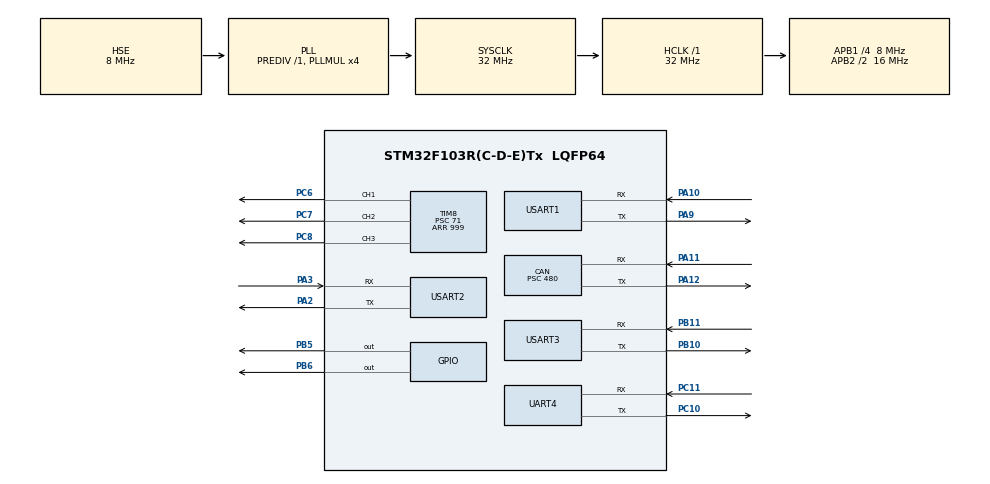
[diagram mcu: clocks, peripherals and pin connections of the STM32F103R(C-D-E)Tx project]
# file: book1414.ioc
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CAN.BS1=CAN_BS1_3TQ
CAN.BS2=CAN_BS2_2TQ
CAN.CalculateBaudRate=2777
CAN.CalculateTimeBit=360000
CAN.CalculateTimeQuantum=60000.0
CAN.Mode=CAN_MODE_LOOPBACK
CAN.Prescaler=480
Mcu.Family=STM32F1
Mcu.Name=STM32F103R(C-D-E)Tx
Mcu.Package=LQFP64
NVIC.PriorityGroup=NVIC_PRIORITYGROUP_4
NVIC.TIM3_IRQn=true\:0\:0\:false\:false\:true\:true\:true\:true
NVIC.TIM8_UP_IRQn=true\:2\:0\:true\:false\:true\:true\:true\:true
NVIC.UART4_IRQn=true\:0\:0\:false\:false\:true\:true\:true\:true
NVIC.USART3_IRQn=true\:0\:0\:false\:false\:true\:true\:true\:true
NVIC.USB_LP_CAN1_RX0_IRQn=true\:0\:0\:false\:false\:true\:true\:true\:true
PA10.Mode=Asynchronous
PA10.Signal=USART1_RX
PA11.Mode=CAN_Activate
PA11.Signal=CAN_RX
PA12.Mode=CAN_Activate
PA12.Signal=CAN_TX
PA2.Mode=Asynchronous
PA2.Signal=USART2_TX
PA3.Mode=Asynchronous
PA3.Signal=USART2_RX
PA9.Mode=Asynchronous
PA9.Signal=USART1_TX
PB10.Mode=Asynchronous
PB10.Signal=USART3_TX
PB11.Mode=Asynchronous
PB11.Signal=USART3_RX
PB5.Signal=GPIO_Output
PB6.Signal=GPIO_Output
PC10.Mode=Asynchronous
PC10.Signal=UART4_TX
PC11.Mode=Asynchronous
PC11.Signal=UART4_RX
PC6.Signal=S_TIM8_CH1
PC7.Signal=S_TIM8_CH2
PC8.Signal=S_TIM8_CH3
PD0-OSC_IN.Mode=HSE-External-Oscillator
PD0-OSC_IN.Signal=RCC_OSC_IN
PD1-OSC_OUT.Mode=HSE-External-Oscillator
PD1-OSC_OUT.Signal=RCC_OSC_OUT
ProjectManager.HeapSize=0x200
ProjectManager.StackSize=0x400
ProjectManager.TargetToolchain=STM32CubeIDE
RCC.AHBFreq_Value=32000000
RCC.APB1CLKDivider=RCC_HCLK_DIV4
RCC.APB1Freq_Value=8000000
RCC.APB1TimFreq_Value=16000000
RCC.APB2CLKDivider=RCC_HCLK_DIV2
RCC.APB2Freq_Value=16000000
RCC.APB2TimFreq_Value=32000000
RCC.HCLKFreq_Value=32000000
RCC.PLLMUL=RCC_PLL_MUL4
RCC.PLLSourceVirtual=RCC_PLLSOURCE_HSE
RCC.SYSCLKFreq_VALUE=32000000
RCC.SYSCLKSource=RCC_SYSCLKSOURCE_PLLCLK
RCC.USBFreq_Value=32000000
SH.S_TIM8_CH1.0=TIM8_CH1,PWM Generation1 CH1
SH.S_TIM8_CH2.0=TIM8_CH2,PWM Generation2 CH2
SH.S_TIM8_CH3.0=TIM8_CH3,PWM Generation3 CH3
TIM3.Period=83
TIM8.Channel-PWM\ Generation1\ CH1=TIM_CHANNEL_1
TIM8.Channel-PWM\ Generation2\ CH2=TIM_CHANNEL_2
TIM8.Channel-PWM\ Generation3\ CH3=TIM_CHANNEL_3
TIM8.Period=999
TIM8.Prescaler=71
TIM8.Pulse-PWM\ Generation1\ CH1=500
TIM8.Pulse-PWM\ Generation2\ CH2=500
TIM8.Pulse-PWM\ Generation3\ CH3=500
TIM8.RepetitionCounter=1
UART4.VirtualMode=Asynchronous
USART1.VirtualMode=VM_ASYNC
USART2.VirtualMode=VM_ASYNC
USART3.VirtualMode=VM_ASYNC
VP_SYS_VS_ND.Mode=No_Debug
VP_TIM3_VS_ClockSourceINT.Mode=Internal
VP_TIM8_VS_ClockSourceINT.Mode=Internal
board=custom

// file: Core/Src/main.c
/* USER CODE BEGIN Header */
/**
  ******************************************************************************
  * @file           : main.c
  * @brief          : Main program body
  ******************************************************************************
  * @attention
  *
  * Copyright (c) 2024 STMicroelectronics.
  * All rights reserved.
  *
  * This software is licensed under terms that can be found in the LICENSE file
  * in the root directory of this software component.
  * If no LICENSE file comes with this software, it is provided AS-IS.
  *
  ******************************************************************************
  */
/* USER CODE END Header */
#include "main.h"

/* USER CODE BEGIN Includes */
#include <stdio.h>
#include "bldc.h"
#include "pid.h"
#include "visualscope.h"

//#include "usb_host.h"

#include "lin_protocol.h"

#include <CanTp_Types.h>
#include "CanTp.h"
#include "CanTp_PBcfg.h"
/* USER CODE END Includes */

 CAN_HandleTypeDef hcan;

TIM_HandleTypeDef htim3;
TIM_HandleTypeDef htim8;

UART_HandleTypeDef huart4;
UART_HandleTypeDef huart1;
UART_HandleTypeDef huart2;
UART_HandleTypeDef huart3;

/* USER CODE BEGIN PV */
#define KEY_PRESSED     0x00
#define KEY_NOT_PRESSED 0x01

uint8_t ubKeyNumber = 0x0;
CAN_TxHeaderTypeDef   TxHeader;
CAN_RxHeaderTypeDef   RxHeader;
uint8_t               TxData[8];
uint8_t               RxData[8];
uint32_t              TxMailbox;

uint16_t adcTemp[64];
uint16_t getCurrent( void );

uint32_t counter = 1;
uint32_t counter_2 = 1;
uint8_t array[100] = {0};
uint32_t alive_sw = 1;

uint64_t counter_timer = 0;
uint32_t read_pin_counter = 0;

const uint8_t rx_size = 20;
uint8_t rx_buff[20] = {0};
uint8_t tx_buff[4] = {0, 1, 2, 3};

uint8_t raw_data[40] = {};
uint8_t raw_index = 0;
//extern uint8_t flag_read_pin;
uint8_t flag_read_pin = 0;

LIN_ERR_t check;

//for dertermine LOGIC level
uint8_t logic_counter = 0;
uint8_t sample_counter = 0; //max = 13
uint8_t dertimine_logic = 0; //max = 13

uint8_t bit_index = 0; //max = 20
uint8_t bit_array[20] = {0};

uint8_t tx_data = 0;
uint8_t rx_data = 0;

LIN_FRAME_t myFrame;
uint8_t uart3_rx_data = 0;
/* USER CODE END PV */

void SystemClock_Config(void);
static void MX_GPIO_Init(void);
static void MX_TIM8_Init(void);
static void MX_CAN_Init(void);
static void MX_USART2_UART_Init(void);
static void MX_USART1_UART_Init(void);
static void MX_TIM3_Init(void);
static void MX_UART4_Init(void);
static void MX_USART3_UART_Init(void);

/* USER CODE BEGIN 0 */
#define rate 999
/* USER CODE END 0 */

int main(void)
{
  /* USER CODE BEGIN 1 */
  uint8_t tx[10];
  int16_t speed;
  /* USER CODE END 1 */

  /* MCU Configuration--------------------------------------------------------*/

  /* Reset of all peripherals, Initializes the Flash interface and the Systick. */
  HAL_Init();

  /* Configure the system clock */
  SystemClock_Config();

  /* Initialize all configured peripherals */
  MX_GPIO_Init();
  //MX_USB_HOST_Init();
  MX_TIM8_Init();
  MX_CAN_Init();
  MX_USART2_UART_Init();
  MX_USART1_UART_Init();
  MX_TIM3_Init();
  MX_UART4_Init();
  MX_USART3_UART_Init();
  /* USER CODE BEGIN 2 */
  printf("App Started\r\n");
  HAL_TIM_Base_Start_IT(&htim3);
  HAL_UART_Receive_IT (&huart4, rx_buff, 20);
  HAL_UART_Receive_IT (&huart3, &uart3_rx_data, 1);
  /* USER CODE END 2 */

  /* Infinite loop */
  while (1)
  {

    /* USER CODE BEGIN 3 */
    /*for (int i=0;i<rate+1;i=i+8){
      TIM1->CCR1=i;
      TIM1->CCR2=rate-i;
      TIM1->CCR3=rate-i;
      if (i%12==0)
        HAL_GPIO_TogglePin(LD2_GPIO_Port, LD2_Pin);
      HAL_Delay(25);
    }
    for (int i=rate+1;i>0;i=i-8){
      TIM1->CCR1=i;
      TIM1->CCR2=rate-i+1;
      TIM1->CCR3=rate-i+1;
      if (i%12==0)
        HAL_GPIO_TogglePin(LD2_GPIO_Port, LD2_Pin);
      HAL_Delay(25);
    }*/

    *(uint16_t *)tx = mymotor.Current;
    *(uint16_t *)(tx+2) = mymotor.SpeedRef;
    if( mymotor.SpeedBck > 32000 ) speed = 32000;
    else if( mymotor.SpeedBck < -32000 ) speed = -32000;
    else speed = mymotor.SpeedBck;
    *(uint16_t *)(tx+4) = speed;  //  锟斤拷锟阶拷锟?? 锟斤拷转/锟斤拷
    CRC16( tx, tx+8, 8 );
    HAL_UART_Transmit(&huart2,tx,10,10);
    HAL_Delay(2);

    while (HAL_GPIO_ReadPin(B1_GPIO_Port, B1_Pin) == KEY_PRESSED)
    {
      if (ubKeyNumber == 0x4)
      {
        ubKeyNumber = 0x00;
      }
      else
      {
        HAL_GPIO_WritePin(LD2_GPIO_Port,LD2_Pin,GPIO_PIN_RESET);

        //MX_USB_HOST_Process();

        if (tx_data == 10) {
          UB_LIN_SendData(&myFrame, &huart3);
          HAL_Delay(100);
          tx_data = 20;
        } else if ( tx_data == 20) {
          //UB_LIN_SendData(&myFrame, &huart3);
          //HAL_Delay(100);
        } else {
          //do nothing
        }

        /* Set the data to be transmitted */
        TxData[0] = 98;//ubKeyNumber;
        TxData[1] = 99;

        /* Start the Transmission process */
        if (HAL_CAN_AddTxMessage(&hcan, &TxHeader, TxData, &TxMailbox) != HAL_OK)
        {
          Error_Handler();
        }
        printf("11111111111111111\r\n");
        HAL_Delay(10);

        while (HAL_GPIO_ReadPin(B1_GPIO_Port, B1_Pin) != KEY_NOT_PRESSED)
        {
        }
      }
    }
  }
  /* USER CODE END 3 */
}

void SystemClock_Config(void)
{
  RCC_OscInitTypeDef RCC_OscInitStruct = {0};
  RCC_ClkInitTypeDef RCC_ClkInitStruct = {0};

  //__HAL_PWR_VOLTAGESCALING_CONFIG(PWR_REGULATOR_VOLTAGE_SCALE1);

  /** Initializes the RCC Oscillators according to the specified parameters
  * in the RCC_OscInitTypeDef structure.
  */
  RCC_OscInitStruct.OscillatorType = RCC_OSCILLATORTYPE_HSE;
  RCC_OscInitStruct.HSEState = RCC_HSE_ON;
  RCC_OscInitStruct.HSEPredivValue = RCC_HSE_PREDIV_DIV1;
  RCC_OscInitStruct.HSIState = RCC_HSI_ON;
  RCC_OscInitStruct.PLL.PLLState = RCC_PLL_ON;
  RCC_OscInitStruct.PLL.PLLSource = RCC_PLLSOURCE_HSE;
  RCC_OscInitStruct.PLL.PLLMUL = RCC_PLL_MUL4;
  //RCC_OscInitStruct.PLL.PLLM = 4;
  //RCC_OscInitStruct.PLL.PLLN = 168;
  //RCC_OscInitStruct.PLL.PLLP = RCC_PLLP_DIV2;
  //RCC_OscInitStruct.PLL.PLLQ = 7;
  if (HAL_RCC_OscConfig(&RCC_OscInitStruct) != HAL_OK)
  {
    Error_Handler();
  }

  /** Initializes the CPU, AHB and APB buses clocks
  */
  RCC_ClkInitStruct.ClockType = RCC_CLOCKTYPE_HCLK|RCC_CLOCKTYPE_SYSCLK
                              |RCC_CLOCKTYPE_PCLK1|RCC_CLOCKTYPE_PCLK2;
  RCC_ClkInitStruct.SYSCLKSource = RCC_SYSCLKSOURCE_PLLCLK;
  RCC_ClkInitStruct.AHBCLKDivider = RCC_SYSCLK_DIV1;
  RCC_ClkInitStruct.APB1CLKDivider = RCC_HCLK_DIV4;
  RCC_ClkInitStruct.APB2CLKDivider = RCC_HCLK_DIV2;

  if (HAL_RCC_ClockConfig(&RCC_ClkInitStruct, FLASH_LATENCY_1) != HAL_OK)
  {
    Error_Handler();
  }
}

static void MX_CAN_Init(void)
{

  /* USER CODE BEGIN CAN_Init 0 */
  CAN_FilterTypeDef  sFilterConfig;
  /* USER CODE END CAN_Init 0 */

  hcan.Instance = CAN1;
  hcan.Init.Prescaler = 480;  //������Ϊ��72M/(480*(1+3+2))=0.25 ��250K
  hcan.Init.Mode = CAN_MODE_LOOPBACK;//CAN_MODE_NORMAL;
  hcan.Init.SyncJumpWidth = CAN_SJW_1TQ;
  hcan.Init.TimeSeg1 = CAN_BS1_3TQ;
  hcan.Init.TimeSeg2 = CAN_BS2_2TQ;
  hcan.Init.TimeTriggeredMode = DISABLE;
  hcan.Init.AutoBusOff = DISABLE;
  hcan.Init.AutoWakeUp = DISABLE;
  hcan.Init.AutoRetransmission = DISABLE;
  hcan.Init.ReceiveFifoLocked = DISABLE;
  hcan.Init.TransmitFifoPriority = DISABLE;
  if (HAL_CAN_Init(&hcan) != HAL_OK)
  {
    Error_Handler();
  }
  /* USER CODE BEGIN CAN_Init 2 */
  /* Configure the CAN Filter */
  sFilterConfig.FilterBank = 0;
  sFilterConfig.FilterMode = CAN_FILTERMODE_IDMASK;
  sFilterConfig.FilterScale = CAN_FILTERSCALE_32BIT;
  sFilterConfig.FilterIdHigh = 0x0000;
  sFilterConfig.FilterIdLow = 0x0000;
  sFilterConfig.FilterMaskIdHigh = 0x0000;
  sFilterConfig.FilterMaskIdLow = 0x0000;
  sFilterConfig.FilterFIFOAssignment = CAN_RX_FIFO0;
  sFilterConfig.FilterActivation = ENABLE;
  //sFilterConfig.SlaveStartFilterBank = 14;

  if (HAL_CAN_ConfigFilter(&hcan, &sFilterConfig) != HAL_OK)
  {
    /* Filter configuration Error */
    Error_Handler();
  }

  /* Start the CAN peripheral */
  if (HAL_CAN_Start(&hcan) != HAL_OK)
  {
    /* Start Error */
    Error_Handler();
  }

  /* Activate CAN RX notification */
  if (HAL_CAN_ActivateNotification(&hcan, CAN_IT_RX_FIFO0_MSG_PENDING) != HAL_OK)
  {
    /* Notification Error */
    Error_Handler();
  }

  /* Configure Transmission process */
  TxHeader.StdId = 0x321;
  TxHeader.ExtId = 0x01;
  TxHeader.RTR = CAN_RTR_DATA;
  TxHeader.IDE = CAN_ID_STD;
  TxHeader.DLC = 2;
  TxHeader.TransmitGlobalTime = DISABLE;
  /* USER CODE END CAN_Init 2 */

}

static void MX_TIM3_Init(void)
{

  TIM_ClockConfigTypeDef sClockSourceConfig = {0};
  TIM_MasterConfigTypeDef sMasterConfig = {0};

  htim3.Instance = TIM3;
  htim3.Init.Prescaler = 0;
  htim3.Init.CounterMode = TIM_COUNTERMODE_UP;
  htim3.Init.Period = 83;
  htim3.Init.ClockDivision = TIM_CLOCKDIVISION_DIV1;
  htim3.Init.AutoReloadPreload = TIM_AUTORELOAD_PRELOAD_DISABLE;
  if (HAL_TIM_Base_Init(&htim3) != HAL_OK)
  {
    Error_Handler();
  }
  sClockSourceConfig.ClockSource = TIM_CLOCKSOURCE_INTERNAL;
  if (HAL_TIM_ConfigClockSource(&htim3, &sClockSourceConfig) != HAL_OK)
  {
    Error_Handler();
  }
  sMasterConfig.MasterOutputTrigger = TIM_TRGO_RESET;
  sMasterConfig.MasterSlaveMode = TIM_MASTERSLAVEMODE_DISABLE;
  if (HAL_TIMEx_MasterConfigSynchronization(&htim3, &sMasterConfig) != HAL_OK)
  {
    Error_Handler();
  }

}

static void MX_TIM8_Init(void)
{

  TIM_ClockConfigTypeDef sClockSourceConfig = {0};
  TIM_MasterConfigTypeDef sMasterConfig = {0};
  TIM_OC_InitTypeDef sConfigOC = {0};
  TIM_BreakDeadTimeConfigTypeDef sBreakDeadTimeConfig = {0};

  htim8.Instance = TIM8;
  htim8.Init.Prescaler = 71;
  htim8.Init.CounterMode = TIM_COUNTERMODE_UP;
  htim8.Init.Period = 999;
  htim8.Init.ClockDivision = TIM_CLOCKDIVISION_DIV1;
  htim8.Init.RepetitionCounter = 1;
  htim8.Init.AutoReloadPreload = TIM_AUTORELOAD_PRELOAD_DISABLE;
  if (HAL_TIM_Base_Init(&htim8) != HAL_OK)
  {
    Error_Handler();
  }
  sClockSourceConfig.ClockSource = TIM_CLOCKSOURCE_INTERNAL;
  if (HAL_TIM_ConfigClockSource(&htim8, &sClockSourceConfig) != HAL_OK)
  {
    Error_Handler();
  }
  if (HAL_TIM_PWM_Init(&htim8) != HAL_OK)
  {
    Error_Handler();
  }
  sMasterConfig.MasterOutputTrigger = TIM_TRGO_RESET;
  sMasterConfig.MasterSlaveMode = TIM_MASTERSLAVEMODE_DISABLE;
  if (HAL_TIMEx_MasterConfigSynchronization(&htim8, &sMasterConfig) != HAL_OK)
  {
    Error_Handler();
  }
  sConfigOC.OCMode = TIM_OCMODE_PWM1;
  sConfigOC.Pulse = 500;
  sConfigOC.OCPolarity = TIM_OCPOLARITY_HIGH;
  sConfigOC.OCNPolarity = TIM_OCNPOLARITY_HIGH;
  sConfigOC.OCFastMode = TIM_OCFAST_DISABLE;
  sConfigOC.OCIdleState = TIM_OCIDLESTATE_RESET;
  sConfigOC.OCNIdleState = TIM_OCNIDLESTATE_RESET;
  if (HAL_TIM_PWM_ConfigChannel(&htim8, &sConfigOC, TIM_CHANNEL_1) != HAL_OK)
  {
    Error_Handler();
  }
  if (HAL_TIM_PWM_ConfigChannel(&htim8, &sConfigOC, TIM_CHANNEL_2) != HAL_OK)
  {
    Error_Handler();
  }
  if (HAL_TIM_PWM_ConfigChannel(&htim8, &sConfigOC, TIM_CHANNEL_3) != HAL_OK)
  {
    Error_Handler();
  }
  sBreakDeadTimeConfig.OffStateRunMode = TIM_OSSR_DISABLE;
  sBreakDeadTimeConfig.OffStateIDLEMode = TIM_OSSI_DISABLE;
  sBreakDeadTimeConfig.LockLevel = TIM_LOCKLEVEL_OFF;
  sBreakDeadTimeConfig.DeadTime = 0;
  sBreakDeadTimeConfig.BreakState = TIM_BREAK_DISABLE;
  sBreakDeadTimeConfig.BreakPolarity = TIM_BREAKPOLARITY_HIGH;
  sBreakDeadTimeConfig.AutomaticOutput = TIM_AUTOMATICOUTPUT_DISABLE;
  if (HAL_TIMEx_ConfigBreakDeadTime(&htim8, &sBreakDeadTimeConfig) != HAL_OK)
  {
    Error_Handler();
  }
  HAL_TIM_MspPostInit(&htim8);

  /*##-5- Start signals generation ###########################################*/
  /*--------------------------------------------------------------------------*/
  /* Start channel 1 */
  if(HAL_TIM_OC_Start(&htim8, TIM_CHANNEL_1) != HAL_OK)
  {
    /* Starting Error */
    Error_Handler();
  }
  /* Start channel 1N */
  if(HAL_TIMEx_OCN_Start(&htim8, TIM_CHANNEL_1) != HAL_OK)
  {
    /* Starting Error */
    Error_Handler();
  }
  /*--------------------------------------------------------------------------*/

  /*--------------------------------------------------------------------------*/
  /* Start channel 2 */
  if(HAL_TIM_OC_Start(&htim8, TIM_CHANNEL_2) != HAL_OK)
  {
    /* Starting Error */
    Error_Handler();
  }
  /* Start channel 2N */
  if(HAL_TIMEx_OCN_Start(&htim8, TIM_CHANNEL_2) != HAL_OK)
  {
    /* Starting Error */
    Error_Handler();
  }
  /*--------------------------------------------------------------------------*/

  /*--------------------------------------------------------------------------*/
  /* Start channel 3 */
  if(HAL_TIM_OC_Start(&htim8, TIM_CHANNEL_3) != HAL_OK)
  {
    /* Starting Error */
    Error_Handler();
  }
  /* Start channel 3N */
  if(HAL_TIMEx_OCN_Start(&htim8, TIM_CHANNEL_3) != HAL_OK)
  {
    /* Starting Error */
    Error_Handler();
  }
  /*--------------------------------------------------------------------------*/

  //TIM1->CCR1 = 100-1;
  //TIM1->CCR2 = 100-1;
  //TIM1->CCR3 = 100-1;
}

static void MX_UART4_Init(void)
{

  huart4.Instance = UART4;
  huart4.Init.BaudRate = 115200;
  huart4.Init.WordLength = UART_WORDLENGTH_8B;
  huart4.Init.StopBits = UART_STOPBITS_1;
  huart4.Init.Parity = UART_PARITY_NONE;
  huart4.Init.Mode = UART_MODE_TX_RX;
  huart4.Init.HwFlowCtl = UART_HWCONTROL_NONE;
  huart4.Init.OverSampling = UART_OVERSAMPLING_16;
  if (HAL_LIN_Init(&huart4, UART_LINBREAKDETECTLENGTH_11B) != HAL_OK)
  {
    Error_Handler();
  }

}

static void MX_USART1_UART_Init(void)
{

  huart1.Instance = USART1;
  huart1.Init.BaudRate = 115200;
  huart1.Init.WordLength = UART_WORDLENGTH_8B;
  huart1.Init.StopBits = UART_STOPBITS_1;
  huart1.Init.Parity = UART_PARITY_NONE;
  huart1.Init.Mode = UART_MODE_TX_RX;
  huart1.Init.HwFlowCtl = UART_HWCONTROL_NONE;
  huart1.Init.OverSampling = UART_OVERSAMPLING_16;
  if (HAL_UART_Init(&huart1) != HAL_OK)
  {
    Error_Handler();
  }

}

static void MX_USART2_UART_Init(void)
{

  huart2.Instance = USART2;
  huart2.Init.BaudRate = 115200;
  huart2.Init.WordLength = UART_WORDLENGTH_8B;
  huart2.Init.StopBits = UART_STOPBITS_1;
  huart2.Init.Parity = UART_PARITY_NONE;
  huart2.Init.Mode = UART_MODE_TX_RX;
  huart2.Init.HwFlowCtl = UART_HWCONTROL_NONE;
  huart2.Init.OverSampling = UART_OVERSAMPLING_16;
  if (HAL_UART_Init(&huart2) != HAL_OK)
  {
    Error_Handler();
  }

}

static void MX_USART3_UART_Init(void)
{

  huart3.Instance = USART3;
  huart3.Init.BaudRate = 115200;
  huart3.Init.WordLength = UART_WORDLENGTH_8B;
  huart3.Init.StopBits = UART_STOPBITS_1;
  huart3.Init.Parity = UART_PARITY_NONE;
  huart3.Init.Mode = UART_MODE_TX_RX;
  huart3.Init.HwFlowCtl = UART_HWCONTROL_NONE;
  huart3.Init.OverSampling = UART_OVERSAMPLING_16;
  if (HAL_LIN_Init(&huart3, UART_LINBREAKDETECTLENGTH_11B) != HAL_OK)
  {
    Error_Handler();
  }

}

static void MX_GPIO_Init(void)
{
  GPIO_InitTypeDef GPIO_InitStruct = {0};

  /* GPIO Ports Clock Enable */
  __HAL_RCC_GPIOD_CLK_ENABLE();
  __HAL_RCC_GPIOA_CLK_ENABLE();
  __HAL_RCC_GPIOB_CLK_ENABLE();
  __HAL_RCC_GPIOC_CLK_ENABLE();

  /*Configure GPIO pin : B1_Pin */
  GPIO_InitStruct.Pin = B1_Pin;
  GPIO_InitStruct.Mode = GPIO_MODE_INPUT;
  GPIO_InitStruct.Pull = GPIO_PULLUP;
  GPIO_InitStruct.Speed = GPIO_SPEED_FREQ_MEDIUM;
  HAL_GPIO_Init(B1_GPIO_Port, &GPIO_InitStruct);

  /*Configure GPIO pin : LD2_Pin */
  GPIO_InitStruct.Pin = LD2_Pin;
  GPIO_InitStruct.Mode = GPIO_MODE_OUTPUT_PP;
  GPIO_InitStruct.Pull = GPIO_PULLUP;
  GPIO_InitStruct.Speed = GPIO_SPEED_FREQ_HIGH;
  HAL_GPIO_Init(LD2_GPIO_Port, &GPIO_InitStruct);

  HAL_GPIO_WritePin(LD2_GPIO_Port, LD2_Pin, GPIO_PIN_SET);

  /*Configure GPIO pin Output Level */
  HAL_GPIO_WritePin(GPIOB, GPIO_PIN_5|GPIO_PIN_6, GPIO_PIN_RESET);

  /*Configure GPIO pins : PB5 PB6 */
  GPIO_InitStruct.Pin = GPIO_PIN_5|GPIO_PIN_6;
  GPIO_InitStruct.Mode = GPIO_MODE_OUTPUT_PP;
  GPIO_InitStruct.Pull = GPIO_NOPULL;
  GPIO_InitStruct.Speed = GPIO_SPEED_FREQ_LOW;
  HAL_GPIO_Init(GPIOB, &GPIO_InitStruct);

}

/* USER CODE BEGIN 4 */
/**
  * @brief  Rx Fifo 0 message pending callback in non blocking mode
  * @param  CanHandle: pointer to a CAN_HandleTypeDef structure that contains
  *         the configuration information for the specified CAN.
  * @retval None
  */
void HAL_CAN_RxFifo0MsgPendingCallback(CAN_HandleTypeDef *CanHandle)
{
  /* Get RX message */
  if (HAL_CAN_GetRxMessage(CanHandle, CAN_RX_FIFO0, &RxHeader, RxData) != HAL_OK)
  {
    /* Reception Error */
    Error_Handler();
  }

  printf("Msg received - Data = %d\r\n", RxData[0]);
  /* Display LEDx */
  if ((RxHeader.StdId == 0x321) && (RxHeader.IDE == CAN_ID_STD) && (RxHeader.DLC == 2))
  {
    HAL_GPIO_WritePin(LD2_GPIO_Port,LD2_Pin,GPIO_PIN_SET);
    //HAL_Delay(15);
    for(int i=0;i<3127*100;i++);
    HAL_GPIO_WritePin(LD2_GPIO_Port,LD2_Pin,GPIO_PIN_RESET);
    //ubKeyNumber = RxData[0];
  }
}

// Callback: timer has rolled over
void HAL_TIM_PeriodElapsedCallback(TIM_HandleTypeDef *htim)
{
  // Check which version of the timer triggered this callback and toggle LED
//  if (htim == &htim3)
//  {
//    if(counter_timer >= 100000) {
//      HAL_GPIO_TogglePin(GPIOD, GPIO_PIN_13);
//      counter_timer = 0;
//    }
//    else {
//      counter_timer++;
//    }
//
////    if (flag_read_pin == 0) { //one time only
////      if (HAL_GPIO_ReadPin (GPIOD, GPIO_PIN_11) == 0) {
////        flag_read_pin = 1;
////      }
////    }
//
//    if (flag_read_pin == 1) {
////      if (raw_index < 38) {
////        raw_data[raw_index] = HAL_GPIO_ReadPin (GPIOD, GPIO_PIN_11);
////        raw_index ++;
////      }
////      read_pin_counter = 0;
//      if (read_pin_counter >= 52) {
//        if (raw_index < 38) {
//          raw_data[raw_index] = HAL_GPIO_ReadPin (GPIOD, GPIO_PIN_11);
//          raw_index ++;
//        }
//        read_pin_counter = 0;
//      } else {
//        read_pin_counter++;
//      }
//
//
//      if(HAL_GPIO_ReadPin (GPIOD, GPIO_PIN_11) == GPIO_PIN_RESET) { //start trigger dertermine LOGIC
//        if (logic_counter == 4) {
//          sample_counter++; //max = 13
//          logic_counter = 0; //max = 4 ->reset
//          // check logic
//          if(HAL_GPIO_ReadPin (GPIOD, GPIO_PIN_11) == GPIO_PIN_RESET) {
//            dertimine_logic++; //adding 1 each time sampling
//          } else {
//            //do nothing
//          }
//          if (dertimine_logic > LOGIC_CONFIRMED) {
//            bit_array[bit_index] = 0;
//          } else {
//            bit_array[bit_index] = 1;
//          }
//          // end check logic
//        }
//        logic_counter++;
//      } else {
//        //do nothing
//      }
//
//    }
//  }
}

void HAL_UART_RxCpltCallback(UART_HandleTypeDef *huart)
{
  counter_2++;
  if (counter_2 >= 1000) counter_2 = 0;
  if(huart->Instance == huart4.Instance) {
    HAL_UART_Receive_IT(&huart4, rx_buff, 10); //You need to toggle a breakpoint on this line!
    uint8_t feedback_data = 10;
    HAL_UART_Transmit(&huart4, &feedback_data, 1, 100);
  }
  if(huart->Instance == huart3.Instance) {
    HAL_UART_Receive_IT(&huart3, &uart3_rx_data, 1);
  }

}

void HAL_GPIO_EXTI_Callback(uint16_t GPIO_Pin)
{
 if (GPIO_Pin == GPIO_PIN_3) //key 1
 {
   tx_data = 10;
//   HAL_UART_Transmit(&huart3, &tx_data, 1, 100);
   myFrame.frame_id=0x01;
   myFrame.data_len=2;
   myFrame.data[0]=0xA1;
   myFrame.data[1]=0xB2;
//   UB_LIN_SendData(&myFrame, &huart3);
//   HAL_GPIO_WritePin(GPIOA, GPIO_PIN_6, 1);
//   HAL_GPIO_WritePin(GPIOA, GPIO_PIN_7, 1);
 }
 else if (GPIO_Pin == GPIO_PIN_4) //key 0
 {
   tx_data = 10;
   myFrame.frame_id=0x05;
   myFrame.data_len=2;
   myFrame.data[0]=0x01;
   myFrame.data[1]=0x02;
//   UB_LIN_SendData(&myFrame, &huart3);
//   HAL_UART_Transmit(&huart3, &tx_data, 1, 100);
//   HAL_GPIO_WritePin(GPIOA, GPIO_PIN_6, 0);
//   HAL_GPIO_WritePin(GPIOA, GPIO_PIN_7, 0);
 }
  else if (GPIO_Pin == GPIO_PIN_5) //key 0
  {
    uint8 rx_data[] = {16, 8, 0xFFu, 0xFFu,
                          0xFFu, 0xFFu, 0xFFu, 0xFFu};
     uint8 tx_data[] = {0xFFu, 0xFFu, 0xFFu, 0xFFu,
                        0xFFu, 0xFFu, 0xFFu, 0xFFu,
                        0xFFu, 0xFFu, 0xFFu, 0xFFu};

     PduInfoType rx_pdu;
     PduInfoType tx_pdu;

     rx_pdu.SduDataPtr = &rx_data[0x00u];
     rx_pdu.MetaDataPtr = NULL_PTR;
     rx_pdu.SduLength = sizeof(rx_data);

     tx_pdu.SduDataPtr = &tx_data[0x00u];
     tx_pdu.MetaDataPtr = NULL_PTR;
     tx_pdu.SduLength = sizeof(tx_data);

     CanTp_Init(&CanTp_Config[0x00u]);
     CanTp_RxIndication(0, &rx_pdu);
     CanTp_MainFunction();
  }
}

Std_ReturnType CanIf_Transmit(PduIdType txPduId, const PduInfoType *pPduInfo)
{
    return E_OK;
}

Std_ReturnType Det_ReportError(uint16 moduleId,
                               uint8 instanceId,
                               uint8 apiId,
                               uint8 errorId)
{
    (void)moduleId;
    (void)instanceId;
    (void)apiId;
    (void)errorId;

    return E_OK;
}

Std_ReturnType Det_ReportRuntimeError(uint16 moduleId,
                                      uint8 instanceId,
                                      uint8 apiId,
                                      uint8 errorId)
{
    (void)moduleId;
    (void)instanceId;
    (void)apiId;
    (void)errorId;

    return E_OK;
}

Std_ReturnType Det_ReportTransientFault(uint16 moduleId,
                                        uint8 instanceId,
                                        uint8 apiId,
                                        uint8 faultId)
{
    (void)moduleId;
    (void)instanceId;
    (void)apiId;
    (void)faultId;

    return E_OK;
}

void PduR_CanTpRxIndication(PduIdType rxPduId, Std_ReturnType result)
{
    (void)rxPduId;
    (void)result;
}

void PduR_CanTpTxConfirmation(PduIdType txPduId, Std_ReturnType result)
{
    (void)txPduId;
    (void)result;
}

BufReq_ReturnType PduR_CanTpCopyRxData(PduIdType rxPduId,
                                       const PduInfoType *pPduInfo,
                                       PduLengthType *pBuffer)
{
    (void)rxPduId;
    (void)pPduInfo;
    (void)pBuffer;

    return E_OK;
}

BufReq_ReturnType PduR_CanTpCopyTxData(PduIdType txPduId,
                                       const PduInfoType *pPduInfo,
                                       const RetryInfoType *pRetryInfo,
                                       PduLengthType *pAvailableData)
{
    (void)txPduId;
    (void)pPduInfo;
    (void)pRetryInfo;
    (void)pAvailableData;

    return E_OK;
}

BufReq_ReturnType PduR_CanTpStartOfReception(PduIdType pduId,
                                             const PduInfoType *pPduInfo,
                                             PduLengthType tpSduLength,
                                             PduLengthType *pBufferSize)
{
    (void)pduId;
    (void)pPduInfo;
    (void)tpSduLength;
    (void)pBufferSize;

    *pBufferSize = 8;

    return E_OK;
}

uint16_t getCurrent( void )
{
  uint8_t i,j=0;
  uint32_t sum = 0;
  uint16_t max = 0;

#if 1

  for( i = 0; i<64; i++ )
  {
    sum += adcTemp[i];
  }
  sum >>= 6;

  return sum;

#else

  for( i = 0; i<64; i++ )
  {
    if( max < adcTemp[i] )  max = adcTemp[i];
  }

  return max;

#endif
}

// 重定向 fputc 函数，将输出重定向到 USART1
int fputc(int ch, FILE *f) {  //MDK
    HAL_UART_Transmit(&huart1, (uint8_t *)&ch, 1, 0xFFFF);

    return ch;
}
__attribute__((weak)) int _write(int file, char *ptr, int len)  //gcc
{
   if(HAL_UART_Transmit(&huart1,ptr,len,0xffff) != HAL_OK)
   {
     Error_Handler();
   }
}
/* USER CODE END 4 */

void Error_Handler(void)
{
  __disable_irq();
  while (1)
  {
  }
}
